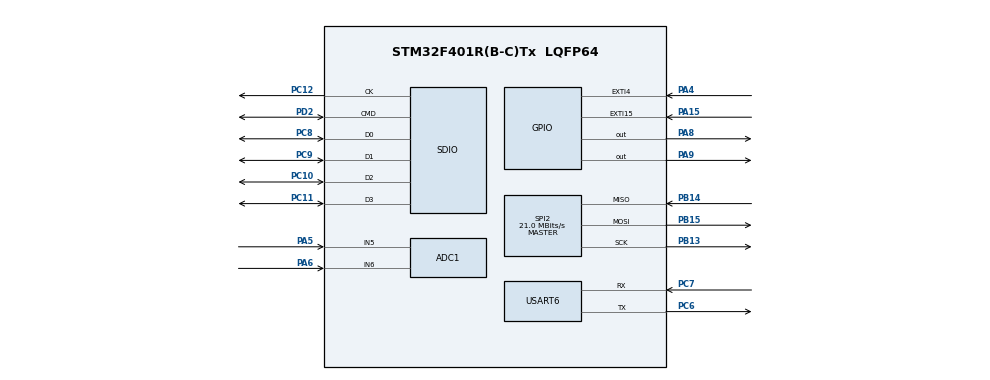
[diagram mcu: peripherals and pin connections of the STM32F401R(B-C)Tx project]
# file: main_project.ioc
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ADC1.Channel-0\#ChannelRegularConversion=ADC_CHANNEL_5
ADC1.NbrOfConversionFlag=1
ADC1.Rank-0\#ChannelRegularConversion=1
ADC1.SamplingTime-0\#ChannelRegularConversion=ADC_SAMPLETIME_3CYCLES
ADC1.master=1
Dma.Request0=USART6_RX
Dma.USART6_RX.0.Direction=DMA_PERIPH_TO_MEMORY
Dma.USART6_RX.0.FIFOMode=DMA_FIFOMODE_ENABLE
Dma.USART6_RX.0.FIFOThreshold=DMA_FIFO_THRESHOLD_FULL
Dma.USART6_RX.0.Instance=DMA2_Stream1
Dma.USART6_RX.0.MemBurst=DMA_MBURST_SINGLE
Dma.USART6_RX.0.MemDataAlignment=DMA_MDATAALIGN_BYTE
Dma.USART6_RX.0.MemInc=DMA_MINC_ENABLE
Dma.USART6_RX.0.Mode=DMA_CIRCULAR
Dma.USART6_RX.0.PeriphBurst=DMA_PBURST_SINGLE
Dma.USART6_RX.0.PeriphDataAlignment=DMA_PDATAALIGN_BYTE
Dma.USART6_RX.0.PeriphInc=DMA_PINC_DISABLE
Dma.USART6_RX.0.Priority=DMA_PRIORITY_MEDIUM
FATFS._MAX_SS=4096
FATFS._USE_LFN=1
Mcu.Family=STM32F4
Mcu.Name=STM32F401R(B-C)Tx
Mcu.Package=LQFP64
NVIC.DMA2_Stream1_IRQn=true\:0\:0\:false\:false\:true\:false\:true
NVIC.EXTI15_10_IRQn=true\:0\:0\:false\:false\:true\:true\:true
NVIC.PriorityGroup=NVIC_PRIORITYGROUP_4
NVIC.USART6_IRQn=true\:0\:0\:false\:false\:true\:true\:true
PA15.Signal=GPXTI15
PA4.Signal=GPXTI4
PA5.Signal=ADCx_IN5
PA6.Signal=ADCx_IN6
PA8.Signal=GPIO_Output
PA9.Signal=GPIO_Output
PB13.Mode=Full_Duplex_Master
PB13.Signal=SPI2_SCK
PB14.Mode=Full_Duplex_Master
PB14.Signal=SPI2_MISO
PB15.Mode=Full_Duplex_Master
PB15.Signal=SPI2_MOSI
PC10.Mode=SD_4_bits_Wide_bus
PC10.Signal=SDIO_D2
PC11.Mode=SD_4_bits_Wide_bus
PC11.Signal=SDIO_D3
PC12.Mode=SD_4_bits_Wide_bus
PC12.Signal=SDIO_CK
PC6.Mode=Asynchronous
PC6.Signal=USART6_TX
PC7.Mode=Asynchronous
PC7.Signal=USART6_RX
PC8.Mode=SD_4_bits_Wide_bus
PC8.Signal=SDIO_D0
PC9.Mode=SD_4_bits_Wide_bus
PC9.Signal=SDIO_D1
PD2.Mode=SD_4_bits_Wide_bus
PD2.Signal=SDIO_CMD
ProjectManager.HeapSize=0x200
ProjectManager.StackSize=0x400
ProjectManager.TargetToolchain=STM32CubeIDE
RCC.48MHZClocksFreq_Value=42000000
RCC.AHBFreq_Value=84000000
RCC.APB1CLKDivider=RCC_HCLK_DIV2
RCC.APB1Freq_Value=42000000
RCC.APB1TimFreq_Value=84000000
RCC.APB2Freq_Value=84000000
RCC.APB2TimFreq_Value=84000000
RCC.CortexFreq_Value=84000000
RCC.HCLKFreq_Value=84000000
RCC.HSE_VALUE=25000000
RCC.HSI_VALUE=16000000
RCC.LSE_VALUE=32768
RCC.PLLM=8
RCC.PLLN=84
RCC.SYSCLKFreq_VALUE=84000000
RCC.SYSCLKSource=RCC_SYSCLKSOURCE_PLLCLK
RCC.VCOOutputFreq_Value=168000000
SH.ADCx_IN5.0=ADC1_IN5,IN5
SH.ADCx_IN6.0=ADC1_IN6,IN6
SPI2.CalculateBaudRate=21.0 MBits/s
SPI2.Direction=SPI_DIRECTION_2LINES
SPI2.Mode=SPI_MODE_MASTER
SPI2.VirtualType=VM_MASTER
USART6.VirtualMode=VM_ASYNC
VP_FATFS_VS_SDIO.Mode=SDIO
board=custom

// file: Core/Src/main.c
/* USER CODE BEGIN Header */
/**
  ******************************************************************************
  * @file           : main.c
  * @brief          : Main program body
  ******************************************************************************
  * @attention
  *
  * Copyright (c) 2022 STMicroelectronics.
  * All rights reserved.
  *
  * This software is licensed under terms that can be found in the LICENSE file
  * in the root directory of this software component.
  * If no LICENSE file comes with this software, it is provided AS-IS.
  *
  ******************************************************************************
  */
/* USER CODE END Header */
#include "main.h"

/* USER CODE BEGIN Includes */
#include "stm32f4xx_hal.h"
#include "app_main.h"
/* USER CODE END Includes */

ADC_HandleTypeDef hadc1;

SD_HandleTypeDef hsd;

SPI_HandleTypeDef hspi2;

void SystemClock_Config(void);
static void MX_GPIO_Init(void);
static void MX_USART6_UART_Init(void);
static void MX_SDIO_SD_Init(void);
static void MX_SPI2_Init(void);
static void MX_DMA_Init(void);
static void MX_ADC1_Init(void);

int main(void)
{

  /* MCU Configuration--------------------------------------------------------*/

  /* Reset of all peripherals, Initializes the Flash interface and the Systick. */
  HAL_Init();

  /* Configure the system clock */
  SystemClock_Config();

  /* Initialize all configured peripherals */
  MX_GPIO_Init();
  MX_USART6_UART_Init();
  MX_SDIO_SD_Init();
  MX_SPI2_Init();
  MX_DMA_Init();
  MX_ADC1_Init();

  /* Infinite loop */
  while (1)
  {

  }
}

void SystemClock_Config(void)
{
  RCC_OscInitTypeDef RCC_OscInitStruct = {0};
  RCC_ClkInitTypeDef RCC_ClkInitStruct = {0};

  /** Configure the main internal regulator output voltage
  */
  __HAL_RCC_PWR_CLK_ENABLE();
  __HAL_PWR_VOLTAGESCALING_CONFIG(PWR_REGULATOR_VOLTAGE_SCALE2);
  /** Initializes the RCC Oscillators according to the specified parameters
  * in the RCC_OscInitTypeDef structure.
  */
  RCC_OscInitStruct.OscillatorType = RCC_OSCILLATORTYPE_HSE;
  RCC_OscInitStruct.HSEState = RCC_HSE_ON;
  RCC_OscInitStruct.PLL.PLLState = RCC_PLL_ON;
  RCC_OscInitStruct.PLL.PLLSource = RCC_PLLSOURCE_HSE;
  RCC_OscInitStruct.PLL.PLLM = 6;
  RCC_OscInitStruct.PLL.PLLN = 84;
  RCC_OscInitStruct.PLL.PLLP = RCC_PLLP_DIV2;
  RCC_OscInitStruct.PLL.PLLQ = 4;
  if (HAL_RCC_OscConfig(&RCC_OscInitStruct) != HAL_OK)
  {
    Error_Handler();
  }
  /** Initializes the CPU, AHB and APB buses clocks
  */
  RCC_ClkInitStruct.ClockType = RCC_CLOCKTYPE_HCLK|RCC_CLOCKTYPE_SYSCLK
                              |RCC_CLOCKTYPE_PCLK1|RCC_CLOCKTYPE_PCLK2;
  RCC_ClkInitStruct.SYSCLKSource = RCC_SYSCLKSOURCE_PLLCLK;
  RCC_ClkInitStruct.AHBCLKDivider = RCC_SYSCLK_DIV1;
  RCC_ClkInitStruct.APB1CLKDivider = RCC_HCLK_DIV2;
  RCC_ClkInitStruct.APB2CLKDivider = RCC_HCLK_DIV1;

  if (HAL_RCC_ClockConfig(&RCC_ClkInitStruct, FLASH_LATENCY_2) != HAL_OK)
  {
    Error_Handler();
  }
}

static void MX_ADC1_Init(void)
{

  ADC_ChannelConfTypeDef sConfig = {0};

  /** Configure the global features of the ADC (Clock, Resolution, Data Alignment and number of conversion)
  */
  hadc1.Instance = ADC1;
  hadc1.Init.ClockPrescaler = ADC_CLOCK_SYNC_PCLK_DIV4;
  hadc1.Init.Resolution = ADC_RESOLUTION_12B;
  hadc1.Init.ScanConvMode = DISABLE;
  hadc1.Init.ContinuousConvMode = DISABLE;
  hadc1.Init.DiscontinuousConvMode = DISABLE;
  hadc1.Init.ExternalTrigConvEdge = ADC_EXTERNALTRIGCONVEDGE_NONE;
  hadc1.Init.ExternalTrigConv = ADC_SOFTWARE_START;
  hadc1.Init.DataAlign = ADC_DATAALIGN_RIGHT;
  hadc1.Init.NbrOfConversion = 1;
  hadc1.Init.DMAContinuousRequests = DISABLE;
  hadc1.Init.EOCSelection = ADC_EOC_SINGLE_CONV;
  if (HAL_ADC_Init(&hadc1) != HAL_OK)
  {
    Error_Handler();
  }
  /** Configure for the selected ADC regular channel its corresponding rank in the sequencer and its sample time.
  */
  sConfig.Channel = ADC_CHANNEL_5;
  sConfig.Rank = 1;
  sConfig.SamplingTime = ADC_SAMPLETIME_3CYCLES;
  if (HAL_ADC_ConfigChannel(&hadc1, &sConfig) != HAL_OK)
  {
    Error_Handler();
  }

}

static void MX_SDIO_SD_Init(void)
{

  hsd.Instance = SDIO;
  hsd.Init.ClockEdge = SDIO_CLOCK_EDGE_RISING;
  hsd.Init.ClockBypass = SDIO_CLOCK_BYPASS_DISABLE;
  hsd.Init.ClockPowerSave = SDIO_CLOCK_POWER_SAVE_DISABLE;
  hsd.Init.BusWide = SDIO_BUS_WIDE_1B;
  hsd.Init.HardwareFlowControl = SDIO_HARDWARE_FLOW_CONTROL_DISABLE;
  hsd.Init.ClockDiv = 0;
  if (HAL_SD_Init(&hsd) != HAL_OK)
  {
    Error_Handler();
  }
  if (HAL_SD_ConfigWideBusOperation(&hsd, SDIO_BUS_WIDE_4B) != HAL_OK)
  {
    Error_Handler();
  }

}

static void MX_SPI2_Init(void)
{

  /* SPI2 parameter configuration*/
  hspi2.Instance = SPI2;
  hspi2.Init.Mode = SPI_MODE_MASTER;
  hspi2.Init.Direction = SPI_DIRECTION_2LINES;
  hspi2.Init.DataSize = SPI_DATASIZE_8BIT;
  hspi2.Init.CLKPolarity = SPI_POLARITY_LOW;
  hspi2.Init.CLKPhase = SPI_PHASE_1EDGE;
  hspi2.Init.NSS = SPI_NSS_SOFT;
  hspi2.Init.BaudRatePrescaler = SPI_BAUDRATEPRESCALER_16;
  hspi2.Init.FirstBit = SPI_FIRSTBIT_MSB;
  hspi2.Init.TIMode = SPI_TIMODE_DISABLE;
  hspi2.Init.CRCCalculation = SPI_CRCCALCULATION_DISABLE;
  hspi2.Init.CRCPolynomial = 10;
  if (HAL_SPI_Init(&hspi2) != HAL_OK)
  {
    Error_Handler();
  }

}

static void MX_USART6_UART_Init(void)
{

  LL_USART_InitTypeDef USART_InitStruct = {0};

  LL_GPIO_InitTypeDef GPIO_InitStruct = {0};

  /* Peripheral clock enable */
  LL_APB2_GRP1_EnableClock(LL_APB2_GRP1_PERIPH_USART6);

  LL_AHB1_GRP1_EnableClock(LL_AHB1_GRP1_PERIPH_GPIOC);
  /**USART6 GPIO Configuration
  PC6   ------> USART6_TX
  PC7   ------> USART6_RX
  */
  GPIO_InitStruct.Pin = LL_GPIO_PIN_6|LL_GPIO_PIN_7;
  GPIO_InitStruct.Mode = LL_GPIO_MODE_ALTERNATE;
  GPIO_InitStruct.Speed = LL_GPIO_SPEED_FREQ_VERY_HIGH;
  GPIO_InitStruct.OutputType = LL_GPIO_OUTPUT_PUSHPULL;
  GPIO_InitStruct.Pull = LL_GPIO_PULL_NO;
  GPIO_InitStruct.Alternate = LL_GPIO_AF_8;
  LL_GPIO_Init(GPIOC, &GPIO_InitStruct);

  /* USART6 DMA Init */

  /* USART6_RX Init */
  LL_DMA_SetChannelSelection(DMA2, LL_DMA_STREAM_1, LL_DMA_CHANNEL_5);

  LL_DMA_SetDataTransferDirection(DMA2, LL_DMA_STREAM_1, LL_DMA_DIRECTION_PERIPH_TO_MEMORY);

  LL_DMA_SetStreamPriorityLevel(DMA2, LL_DMA_STREAM_1, LL_DMA_PRIORITY_MEDIUM);

  LL_DMA_SetMode(DMA2, LL_DMA_STREAM_1, LL_DMA_MODE_CIRCULAR);

  LL_DMA_SetPeriphIncMode(DMA2, LL_DMA_STREAM_1, LL_DMA_PERIPH_NOINCREMENT);

  LL_DMA_SetMemoryIncMode(DMA2, LL_DMA_STREAM_1, LL_DMA_MEMORY_INCREMENT);

  LL_DMA_SetPeriphSize(DMA2, LL_DMA_STREAM_1, LL_DMA_PDATAALIGN_BYTE);

  LL_DMA_SetMemorySize(DMA2, LL_DMA_STREAM_1, LL_DMA_MDATAALIGN_BYTE);

  LL_DMA_DisableFifoMode(DMA2, LL_DMA_STREAM_1);

  USART_InitStruct.BaudRate = 9600;
  USART_InitStruct.DataWidth = LL_USART_DATAWIDTH_8B;
  USART_InitStruct.StopBits = LL_USART_STOPBITS_1;
  USART_InitStruct.Parity = LL_USART_PARITY_NONE;
  USART_InitStruct.TransferDirection = LL_USART_DIRECTION_RX;
  USART_InitStruct.HardwareFlowControl = LL_USART_HWCONTROL_NONE;
  USART_InitStruct.OverSampling = LL_USART_OVERSAMPLING_16;
  LL_USART_Init(USART6, &USART_InitStruct);
  LL_USART_ConfigAsyncMode(USART6);
  LL_USART_Enable(USART6);

}

static void MX_DMA_Init(void)
{

  /* DMA controller clock enable */
  __HAL_RCC_DMA2_CLK_ENABLE();

  /* DMA interrupt init */
  /* DMA2_Stream1_IRQn interrupt configuration */
  NVIC_SetPriority(DMA2_Stream1_IRQn, NVIC_EncodePriority(NVIC_GetPriorityGrouping(),0, 0));
  NVIC_EnableIRQ(DMA2_Stream1_IRQn);

}

static void MX_GPIO_Init(void)
{
  GPIO_InitTypeDef GPIO_InitStruct = {0};

  /* GPIO Ports Clock Enable */
  __HAL_RCC_GPIOC_CLK_ENABLE();
  __HAL_RCC_GPIOH_CLK_ENABLE();
  __HAL_RCC_GPIOA_CLK_ENABLE();
  __HAL_RCC_GPIOB_CLK_ENABLE();
  __HAL_RCC_GPIOD_CLK_ENABLE();

  /*Configure GPIO pin Output Level */
  HAL_GPIO_WritePin(GPIOA, GPIO_PIN_8|GPIO_PIN_9, GPIO_PIN_RESET);

  /*Configure GPIO pins : PA4 PA15 */
  GPIO_InitStruct.Pin = GPIO_PIN_4|GPIO_PIN_15;
  GPIO_InitStruct.Mode = GPIO_MODE_IT_RISING;
  GPIO_InitStruct.Pull = GPIO_NOPULL;
  HAL_GPIO_Init(GPIOA, &GPIO_InitStruct);

  /*Configure GPIO pins : PA8 PA9 */
  GPIO_InitStruct.Pin = GPIO_PIN_8|GPIO_PIN_9;
  GPIO_InitStruct.Mode = GPIO_MODE_OUTPUT_PP;
  GPIO_InitStruct.Pull = GPIO_NOPULL;
  GPIO_InitStruct.Speed = GPIO_SPEED_FREQ_LOW;
  HAL_GPIO_Init(GPIOA, &GPIO_InitStruct);

  /* EXTI interrupt init*/
  HAL_NVIC_SetPriority(EXTI15_10_IRQn, 0, 0);
  HAL_NVIC_EnableIRQ(EXTI15_10_IRQn);

}

void Error_Handler(void)
{
  __disable_irq();
  while (1)
  {
  }
}
